VERSION 5.7 ;
  NOWIREEXTENSIONATPIN ON ;
  DIVIDERCHAR "/" ;
  BUSBITCHARS "[]" ;
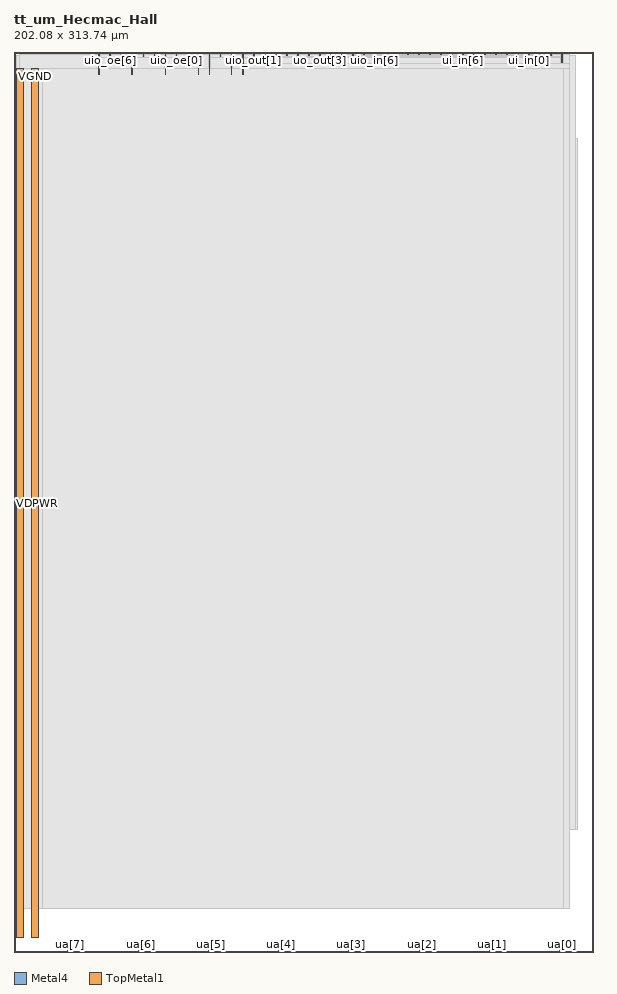
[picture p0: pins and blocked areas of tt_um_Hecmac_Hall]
MACRO tt_um_Hecmac_Hall
  CLASS BLOCK ;
  FOREIGN tt_um_Hecmac_Hall ;
  ORIGIN 0.000 0.000 ;
  SIZE 202.080 BY 313.740 ;
  PIN clk
    DIRECTION INPUT ;
    USE SIGNAL ;
    ANTENNAGATEAREA 1.450800 ;
    PORT
      LAYER Metal4 ;
        RECT 187.050 312.400 187.350 313.740 ;
    END
  END clk
  PIN ena
    DIRECTION INPUT ;
    USE SIGNAL ;
    PORT
      LAYER Metal4 ;
        RECT 190.890 310.000 191.190 313.740 ;
    END
  END ena
  PIN rst_n
    DIRECTION INPUT ;
    USE SIGNAL ;
    ANTENNAGATEAREA 0.180700 ;
    PORT
      LAYER Metal4 ;
        RECT 183.210 312.400 183.510 313.740 ;
    END
  END rst_n
  PIN ua[0]
    DIRECTION INOUT ;
    USE SIGNAL ;
    PORT
      LAYER TopMetal1 ;
        RECT 190.165 0.000 191.915 2.000 ;
    END
  END ua[0]
  PIN ua[1]
    DIRECTION INOUT ;
    USE SIGNAL ;
    PORT
      LAYER TopMetal1 ;
        RECT 165.685 0.000 167.435 2.000 ;
    END
  END ua[1]
  PIN ua[2]
    DIRECTION INOUT ;
    USE SIGNAL ;
    PORT
      LAYER TopMetal1 ;
        RECT 141.205 0.000 142.955 2.000 ;
    END
  END ua[2]
  PIN ua[3]
    DIRECTION INOUT ;
    USE SIGNAL ;
    PORT
      LAYER TopMetal1 ;
        RECT 116.725 0.000 118.475 2.000 ;
    END
  END ua[3]
  PIN ua[4]
    DIRECTION INOUT ;
    USE SIGNAL ;
    PORT
      LAYER TopMetal1 ;
        RECT 92.245 0.000 93.995 2.000 ;
    END
  END ua[4]
  PIN ua[5]
    DIRECTION INOUT ;
    USE SIGNAL ;
    PORT
      LAYER TopMetal1 ;
        RECT 67.765 0.000 69.515 2.000 ;
    END
  END ua[5]
  PIN ua[6]
    DIRECTION INOUT ;
    USE SIGNAL ;
    PORT
      LAYER TopMetal1 ;
        RECT 43.285 0.000 45.035 2.000 ;
    END
  END ua[6]
  PIN ua[7]
    DIRECTION INOUT ;
    USE SIGNAL ;
    PORT
      LAYER TopMetal1 ;
        RECT 18.805 0.000 20.555 2.000 ;
    END
  END ua[7]
  PIN ui_in[0]
    DIRECTION INPUT ;
    USE SIGNAL ;
    PORT
      LAYER Metal4 ;
        RECT 179.370 312.740 179.670 313.740 ;
    END
  END ui_in[0]
  PIN ui_in[1]
    DIRECTION INPUT ;
    USE SIGNAL ;
    PORT
      LAYER Metal4 ;
        RECT 175.530 312.740 175.830 313.740 ;
    END
  END ui_in[1]
  PIN ui_in[2]
    DIRECTION INPUT ;
    USE SIGNAL ;
    PORT
      LAYER Metal4 ;
        RECT 171.690 312.740 171.990 313.740 ;
    END
  END ui_in[2]
  PIN ui_in[3]
    DIRECTION INPUT ;
    USE SIGNAL ;
    PORT
      LAYER Metal4 ;
        RECT 167.850 312.740 168.150 313.740 ;
    END
  END ui_in[3]
  PIN ui_in[4]
    DIRECTION INPUT ;
    USE SIGNAL ;
    PORT
      LAYER Metal4 ;
        RECT 164.010 312.740 164.310 313.740 ;
    END
  END ui_in[4]
  PIN ui_in[5]
    DIRECTION INPUT ;
    USE SIGNAL ;
    PORT
      LAYER Metal4 ;
        RECT 160.170 312.740 160.470 313.740 ;
    END
  END ui_in[5]
  PIN ui_in[6]
    DIRECTION INPUT ;
    USE SIGNAL ;
    PORT
      LAYER Metal4 ;
        RECT 156.330 312.740 156.630 313.740 ;
    END
  END ui_in[6]
  PIN ui_in[7]
    DIRECTION INPUT ;
    USE SIGNAL ;
    PORT
      LAYER Metal4 ;
        RECT 152.490 312.740 152.790 313.740 ;
    END
  END ui_in[7]
  PIN uio_in[0]
    DIRECTION INPUT ;
    USE SIGNAL ;
    PORT
      LAYER Metal4 ;
        RECT 148.650 312.740 148.950 313.740 ;
    END
  END uio_in[0]
  PIN uio_in[1]
    DIRECTION INPUT ;
    USE SIGNAL ;
    PORT
      LAYER Metal4 ;
        RECT 144.810 312.740 145.110 313.740 ;
    END
  END uio_in[1]
  PIN uio_in[2]
    DIRECTION INPUT ;
    USE SIGNAL ;
    PORT
      LAYER Metal4 ;
        RECT 140.970 312.740 141.270 313.740 ;
    END
  END uio_in[2]
  PIN uio_in[3]
    DIRECTION INPUT ;
    USE SIGNAL ;
    PORT
      LAYER Metal4 ;
        RECT 137.130 312.740 137.430 313.740 ;
    END
  END uio_in[3]
  PIN uio_in[4]
    DIRECTION INPUT ;
    USE SIGNAL ;
    PORT
      LAYER Metal4 ;
        RECT 133.290 312.740 133.590 313.740 ;
    END
  END uio_in[4]
  PIN uio_in[5]
    DIRECTION INPUT ;
    USE SIGNAL ;
    PORT
      LAYER Metal4 ;
        RECT 129.450 312.740 129.750 313.740 ;
    END
  END uio_in[5]
  PIN uio_in[6]
    DIRECTION INPUT ;
    USE SIGNAL ;
    PORT
      LAYER Metal4 ;
        RECT 125.610 312.740 125.910 313.740 ;
    END
  END uio_in[6]
  PIN uio_in[7]
    DIRECTION INPUT ;
    USE SIGNAL ;
    PORT
      LAYER Metal4 ;
        RECT 121.770 312.740 122.070 313.740 ;
    END
  END uio_in[7]
  PIN uio_oe[0]
    DIRECTION OUTPUT ;
    USE SIGNAL ;
    ANTENNAGATEAREA 25.000000 ;
    ANTENNADIFFAREA 2271.989014 ;
    PORT
      LAYER Metal4 ;
        RECT 56.490 312.000 56.790 313.740 ;
    END
  END uio_oe[0]
  PIN uio_oe[1]
    DIRECTION OUTPUT ;
    USE SIGNAL ;
    ANTENNAGATEAREA 25.000000 ;
    ANTENNADIFFAREA 2271.989014 ;
    PORT
      LAYER Metal4 ;
        RECT 52.650 306.000 52.950 313.740 ;
    END
  END uio_oe[1]
  PIN uio_oe[2]
    DIRECTION OUTPUT ;
    USE SIGNAL ;
    ANTENNAGATEAREA 25.000000 ;
    ANTENNADIFFAREA 2271.989014 ;
    PORT
      LAYER Metal4 ;
        RECT 48.810 312.000 49.110 313.740 ;
    END
  END uio_oe[2]
  PIN uio_oe[3]
    DIRECTION OUTPUT ;
    USE SIGNAL ;
    ANTENNAGATEAREA 25.000000 ;
    ANTENNADIFFAREA 2271.989014 ;
    PORT
      LAYER Metal4 ;
        RECT 44.970 312.000 45.270 313.740 ;
    END
  END uio_oe[3]
  PIN uio_oe[4]
    DIRECTION OUTPUT ;
    USE SIGNAL ;
    ANTENNAGATEAREA 25.000000 ;
    ANTENNADIFFAREA 2271.989014 ;
    PORT
      LAYER Metal4 ;
        RECT 41.130 306.000 41.430 313.740 ;
    END
  END uio_oe[4]
  PIN uio_oe[5]
    DIRECTION OUTPUT ;
    USE SIGNAL ;
    ANTENNAGATEAREA 25.000000 ;
    ANTENNADIFFAREA 2271.989014 ;
    PORT
      LAYER Metal4 ;
        RECT 37.290 312.000 37.590 313.740 ;
    END
  END uio_oe[5]
  PIN uio_oe[6]
    DIRECTION OUTPUT ;
    USE SIGNAL ;
    ANTENNAGATEAREA 25.000000 ;
    ANTENNADIFFAREA 2271.989014 ;
    PORT
      LAYER Metal4 ;
        RECT 33.450 312.000 33.750 313.740 ;
    END
  END uio_oe[6]
  PIN uio_oe[7]
    DIRECTION OUTPUT ;
    USE SIGNAL ;
    ANTENNAGATEAREA 25.000000 ;
    ANTENNADIFFAREA 2271.989014 ;
    PORT
      LAYER Metal4 ;
        RECT 29.610 306.000 29.910 313.740 ;
    END
  END uio_oe[7]
  PIN uio_out[0]
    DIRECTION OUTPUT ;
    USE SIGNAL ;
    PORT
      LAYER Metal4 ;
        RECT 87.210 312.000 87.510 313.740 ;
    END
  END uio_out[0]
  PIN uio_out[1]
    DIRECTION OUTPUT ;
    USE SIGNAL ;
    PORT
      LAYER Metal4 ;
        RECT 83.370 312.000 83.670 313.740 ;
    END
  END uio_out[1]
  PIN uio_out[2]
    DIRECTION OUTPUT ;
    USE SIGNAL ;
    PORT
      LAYER Metal4 ;
        RECT 79.530 306.000 79.830 313.740 ;
    END
  END uio_out[2]
  PIN uio_out[3]
    DIRECTION OUTPUT ;
    USE SIGNAL ;
    PORT
      LAYER Metal4 ;
        RECT 75.690 306.000 75.990 313.740 ;
    END
  END uio_out[3]
  PIN uio_out[4]
    DIRECTION OUTPUT ;
    USE SIGNAL ;
    PORT
      LAYER Metal4 ;
        RECT 71.850 312.000 72.150 313.740 ;
    END
  END uio_out[4]
  PIN uio_out[5]
    DIRECTION OUTPUT ;
    USE SIGNAL ;
    PORT
      LAYER Metal4 ;
        RECT 68.010 306.000 68.310 313.740 ;
    END
  END uio_out[5]
  PIN uio_out[6]
    DIRECTION OUTPUT ;
    USE SIGNAL ;
    PORT
      LAYER Metal4 ;
        RECT 64.170 306.000 64.470 313.740 ;
    END
  END uio_out[6]
  PIN uio_out[7]
    DIRECTION OUTPUT ;
    USE SIGNAL ;
    PORT
      LAYER Metal4 ;
        RECT 60.330 312.000 60.630 313.740 ;
    END
  END uio_out[7]
  PIN uo_out[0]
    DIRECTION OUTPUT ;
    USE SIGNAL ;
    ANTENNADIFFAREA 0.708600 ;
    PORT
      LAYER Metal4 ;
        RECT 117.930 312.400 118.230 313.740 ;
    END
  END uo_out[0]
  PIN uo_out[1]
    DIRECTION OUTPUT ;
    USE SIGNAL ;
    ANTENNADIFFAREA 0.708600 ;
    PORT
      LAYER Metal4 ;
        RECT 114.090 312.400 114.390 313.740 ;
    END
  END uo_out[1]
  PIN uo_out[2]
    DIRECTION OUTPUT ;
    USE SIGNAL ;
    ANTENNADIFFAREA 0.708600 ;
    PORT
      LAYER Metal4 ;
        RECT 110.250 312.400 110.550 313.740 ;
    END
  END uo_out[2]
  PIN uo_out[3]
    DIRECTION OUTPUT ;
    USE SIGNAL ;
    ANTENNADIFFAREA 0.708600 ;
    PORT
      LAYER Metal4 ;
        RECT 106.410 312.400 106.710 313.740 ;
    END
  END uo_out[3]
  PIN uo_out[4]
    DIRECTION OUTPUT ;
    USE SIGNAL ;
    ANTENNADIFFAREA 0.708600 ;
    PORT
      LAYER Metal4 ;
        RECT 102.570 312.400 102.870 313.740 ;
    END
  END uo_out[4]
  PIN uo_out[5]
    DIRECTION OUTPUT ;
    USE SIGNAL ;
    ANTENNADIFFAREA 0.708600 ;
    PORT
      LAYER Metal4 ;
        RECT 98.730 312.400 99.030 313.740 ;
    END
  END uo_out[5]
  PIN uo_out[6]
    DIRECTION OUTPUT ;
    USE SIGNAL ;
    ANTENNADIFFAREA 0.708600 ;
    PORT
      LAYER Metal4 ;
        RECT 94.890 312.400 95.190 313.740 ;
    END
  END uo_out[6]
  PIN uo_out[7]
    DIRECTION OUTPUT ;
    USE SIGNAL ;
    ANTENNADIFFAREA 0.708600 ;
    PORT
      LAYER Metal4 ;
        RECT 91.050 312.400 91.350 313.740 ;
    END
  END uo_out[7]
  PIN VDPWR
    DIRECTION INOUT ;
    USE POWER ;
    PORT
      LAYER TopMetal1 ;
        RECT 1.000 5.000 3.400 308.000 ;
    END
  END VDPWR
  PIN VGND
    DIRECTION INOUT ;
    USE GROUND ;
    PORT
      LAYER TopMetal1 ;
        RECT 6.000 5.000 8.400 308.000 ;
    END
  END VGND
  OBS
      LAYER GatPoly ;
        RECT 21.585 42.600 195.600 283.310 ;
      LAYER Metal1 ;
        RECT 1.000 42.650 196.600 283.500 ;
      LAYER Metal2 ;
        RECT 1.960 42.650 195.600 312.500 ;
      LAYER Metal3 ;
        RECT 1.000 43.500 193.455 312.500 ;
      LAYER Metal4 ;
        RECT 1.960 305.790 29.400 312.800 ;
        RECT 30.120 311.790 33.240 312.800 ;
        RECT 33.960 311.790 37.080 312.800 ;
        RECT 37.800 311.790 40.920 312.800 ;
        RECT 30.120 305.790 40.920 311.790 ;
        RECT 41.640 311.790 44.760 312.800 ;
        RECT 45.480 311.790 48.600 312.800 ;
        RECT 49.320 311.790 52.440 312.800 ;
        RECT 41.640 305.790 52.440 311.790 ;
        RECT 53.160 311.790 56.280 312.800 ;
        RECT 57.000 311.790 60.120 312.800 ;
        RECT 60.840 311.790 63.960 312.800 ;
        RECT 53.160 305.790 63.960 311.790 ;
        RECT 64.680 305.790 67.800 312.800 ;
        RECT 68.520 311.790 71.640 312.800 ;
        RECT 72.360 311.790 75.480 312.800 ;
        RECT 68.520 305.790 75.480 311.790 ;
        RECT 76.200 305.790 79.320 312.800 ;
        RECT 80.040 311.790 83.160 312.800 ;
        RECT 83.880 311.790 87.000 312.800 ;
        RECT 87.720 312.190 90.840 312.800 ;
        RECT 91.560 312.190 94.680 312.800 ;
        RECT 95.400 312.190 98.520 312.800 ;
        RECT 99.240 312.190 102.360 312.800 ;
        RECT 103.080 312.190 106.200 312.800 ;
        RECT 106.920 312.190 110.040 312.800 ;
        RECT 110.760 312.190 113.880 312.800 ;
        RECT 114.600 312.190 117.720 312.800 ;
        RECT 118.440 312.530 121.560 312.800 ;
        RECT 122.280 312.530 125.400 312.800 ;
        RECT 126.120 312.530 129.240 312.800 ;
        RECT 129.960 312.530 133.080 312.800 ;
        RECT 133.800 312.530 136.920 312.800 ;
        RECT 137.640 312.530 140.760 312.800 ;
        RECT 141.480 312.530 144.600 312.800 ;
        RECT 145.320 312.530 148.440 312.800 ;
        RECT 149.160 312.530 152.280 312.800 ;
        RECT 153.000 312.530 156.120 312.800 ;
        RECT 156.840 312.530 159.960 312.800 ;
        RECT 160.680 312.530 163.800 312.800 ;
        RECT 164.520 312.530 167.640 312.800 ;
        RECT 168.360 312.530 171.480 312.800 ;
        RECT 172.200 312.530 175.320 312.800 ;
        RECT 176.040 312.530 179.160 312.800 ;
        RECT 179.880 312.530 183.000 312.800 ;
        RECT 118.440 312.190 183.000 312.530 ;
        RECT 183.720 312.190 186.840 312.800 ;
        RECT 187.560 312.190 190.680 312.800 ;
        RECT 87.720 311.790 190.680 312.190 ;
        RECT 80.040 309.790 190.680 311.790 ;
        RECT 191.400 309.790 193.500 312.800 ;
        RECT 80.040 305.790 193.500 309.790 ;
        RECT 1.960 44.415 193.500 305.790 ;
      LAYER Metal5 ;
        RECT 1.000 15.000 193.600 308.000 ;
      LAYER TopMetal1 ;
        RECT 10.040 15.000 191.720 308.000 ;
  END
END tt_um_Hecmac_Hall
END LIBRARY

